VERSION 5.7 ;
  NOWIREEXTENSIONATPIN ON ;
  DIVIDERCHAR "/" ;
  BUSBITCHARS "[]" ;
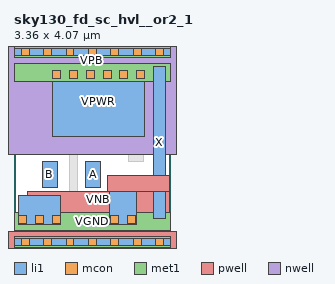
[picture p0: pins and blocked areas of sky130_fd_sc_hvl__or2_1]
MACRO sky130_fd_sc_hvl__or2_1
  CLASS BLOCK ;
  FOREIGN sky130_fd_sc_hvl__or2_1 ;
  ORIGIN 0.000 0.000 ;
  SIZE 3.360 BY 4.070 ;
  PIN A
    ANTENNAGATEAREA 0.420000 ;
    PORT
      LAYER li1 ;
        RECT 1.530 1.175 1.860 1.725 ;
    END
  END A
  PIN B
    ANTENNAGATEAREA 0.420000 ;
    PORT
      LAYER li1 ;
        RECT 0.605 1.175 0.935 1.725 ;
    END
  END B
  PIN VGND
    USE GROUND ;
    PORT
      LAYER li1 ;
        RECT 0.090 0.365 1.000 0.995 ;
        RECT 2.040 0.365 2.630 1.325 ;
      LAYER mcon ;
        RECT 0.100 0.395 0.270 0.565 ;
        RECT 0.460 0.395 0.630 0.565 ;
        RECT 0.820 0.395 0.990 0.565 ;
        RECT 2.070 0.395 2.240 0.565 ;
        RECT 2.430 0.395 2.600 0.565 ;
      LAYER met1 ;
        RECT 0.000 0.255 3.360 0.625 ;
    END
  END VGND
  PIN VNB
    ANTENNADIFFAREA 0.571200 ;
    PORT
      LAYER pwell ;
        RECT 2.010 1.085 3.340 1.415 ;
        RECT 0.290 0.215 3.340 1.085 ;
        RECT -0.130 -0.215 3.490 0.215 ;
      LAYER li1 ;
        RECT 0.000 -0.085 3.360 0.085 ;
      LAYER mcon ;
        RECT 0.155 -0.085 0.325 0.085 ;
        RECT 0.635 -0.085 0.805 0.085 ;
        RECT 1.115 -0.085 1.285 0.085 ;
        RECT 1.595 -0.085 1.765 0.085 ;
        RECT 2.075 -0.085 2.245 0.085 ;
        RECT 2.555 -0.085 2.725 0.085 ;
        RECT 3.035 -0.085 3.205 0.085 ;
      LAYER met1 ;
        RECT 0.000 -0.115 3.360 0.115 ;
    END
  END VNB
  PIN VPB
    ANTENNADIFFAREA 0.571200 ;
    PORT
      LAYER nwell ;
        RECT -0.330 1.885 3.690 4.485 ;
      LAYER li1 ;
        RECT 0.000 3.985 3.360 4.155 ;
      LAYER mcon ;
        RECT 0.155 3.985 0.325 4.155 ;
        RECT 0.635 3.985 0.805 4.155 ;
        RECT 1.115 3.985 1.285 4.155 ;
        RECT 1.595 3.985 1.765 4.155 ;
        RECT 2.075 3.985 2.245 4.155 ;
        RECT 2.555 3.985 2.725 4.155 ;
        RECT 3.035 3.985 3.205 4.155 ;
      LAYER met1 ;
        RECT 0.000 3.955 3.360 4.185 ;
    END
  END VPB
  PIN VPWR
    USE POWER ;
    PORT
      LAYER li1 ;
        RECT 0.830 2.255 2.800 3.755 ;
      LAYER mcon ;
        RECT 0.830 3.505 1.000 3.675 ;
        RECT 1.190 3.505 1.360 3.675 ;
        RECT 1.550 3.505 1.720 3.675 ;
        RECT 1.910 3.505 2.080 3.675 ;
        RECT 2.270 3.505 2.440 3.675 ;
        RECT 2.630 3.505 2.800 3.675 ;
      LAYER met1 ;
        RECT 0.000 3.445 3.360 3.815 ;
    END
  END VPWR
  PIN X
    ANTENNADIFFAREA 0.641250 ;
    PORT
      LAYER li1 ;
        RECT 2.980 0.495 3.235 3.755 ;
    END
  END X
  OBS
      LAYER li1 ;
        RECT 0.400 2.075 0.650 2.675 ;
        RECT 0.400 1.905 2.775 2.075 ;
        RECT 1.180 0.995 1.350 1.905 ;
        RECT 2.445 1.725 2.775 1.905 ;
        RECT 1.180 0.495 1.510 0.995 ;
  END
END sky130_fd_sc_hvl__or2_1
END LIBRARY

